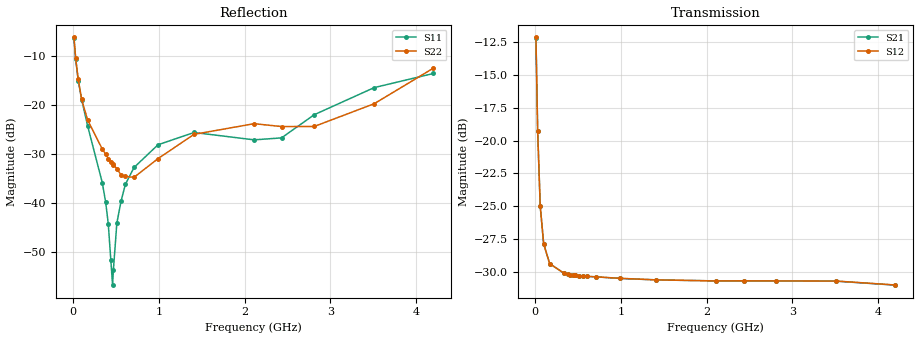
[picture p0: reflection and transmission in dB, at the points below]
! Integrated Device Technology
! Corporate Headquarters
! 6024 Silver Creek Valley Road
! San Jose, CA 95138  USA
! Phone:  1-408-284-8200
! Toll Free:  1-800-223-1366
! Webpage:  http://www.idt.com/
! Timing and RF Division
! 515 Groton Road, Suite 102
! Westford, MA 01886-6024
! Device:  F1950
! Description: 7-bit 0.25 dB Digital Step Attenuator
! Frequency:  150.0 -  4000.00 MHz
! Package:  4x4 mm Thin QFN Plastic Package: 24 pin
! Ports:  2 RF, 12 DC
!  Pin  1  = D0
!  Pin  2  = VDD
!  Pin  3  = Vmode
!  Pin  4  = GND
!  Pin  5  = RF1  =  Port 1
!  Pin  6  = GND
!  Pin  7  = GND
!  Pin  8  = GND
!  Pin  9  = GND
!  Pin 10  = GND
!  Pin 11  = GND
!  Pin 12  = GND
!  Pin 13  = GND
!  Pin 14  = RF2  =  Port 2
!  Pin 15  = GND
!  Pin 16  = LE
!  Pin 17  = CLK
!  Pin 18  = DATE
!  Pin 19  = D6
!  Pin 20  = D5
!  Pin 21  = D4
!  Pin 22  = D3
!  Pin 23  = D2
!  Pin 24  = D1
! State:  118
! Atten State:  29.50 dB
! Voltage:  +5.00 Volts
! Current:  Not Measured mA
! Data:  The device was measured on a the F195X evaluation board which has
!  individual transmission lines to the RF pins.  Data was collected
!  using a calibrated network analyzer.  The evaluation board was
!  de-embedded using a TRL calibration technique.
!  The reference plane is the edge of the package pin.
! Misc:  Board 2019
!  Action Tracker AT0250
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# GHz S dB R 50
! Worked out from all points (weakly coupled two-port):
!   420 points, 10 MHz to 4.2 GHz, reference 50 ohm
!   highest |S21| = -12.14 dB at 10 MHz (marker M1); lowest = -31.0 dB at 4.2 GHz (marker M2)
!   lowest |S11| = -56.7 dB at 460 MHz (marker M3), VSWR 1.00, Z = 49.9 - j0.0336 ohm
!   |S11| at or under -10 dB: 26.67 MHz to end of sweep
!   |S22| runs from -35.0 to -6.2 dB; largest |S21 - S12| = 7.1e-05
!   S11 on the Smith chart (normalised r, x): 10 MHz: 1.96, -1.18; 30 MHz: 1.28, -0.64; 60 MHz: 1.11, -0.36; 410 MHz: 1.00, -0.01; 4.2 GHz: 0.69, +0.17
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0.01  -6.41 -29.1  -12.14 -42.3  -12.13 -42.2  -6.21 -29.8
0.03  -10.64 -51.0  -19.27 -62.6  -19.27 -62.6  -10.49 -53.0
0.06  -15.03 -63.6  -24.99 -55.9  -24.99 -55.9  -14.78 -65.6
0.1  -18.90 -70.4  -27.87 -42.2  -27.87 -42.2  -18.86 -71.2
0.17  -24.29 -71.9  -29.38 -28.5  -29.39 -28.5  -23.07 -77.0
0.34  -35.79 -70.3  -30.13 -17.3  -30.12 -17.3  -28.96 -85.9
0.38  -39.83 -70.1  -30.18 -16.3  -30.19 -16.3  -29.99 -87.6
0.41  -44.18 -76.7  -30.22 -15.6  -30.22 -15.7  -30.88 -89.2
0.44  -51.63 -96.9  -30.25 -15.1  -30.25 -15.1  -31.69 -93.4
0.46  -56.67 -166.7  -30.26 -14.9  -30.26 -14.9  -32.09 -96.8
0.47  -53.50 159.1  -30.27 -14.7  -30.27 -14.7  -32.24 -98.5
0.51  -44.03 137.8  -30.30 -14.3  -30.30 -14.3  -32.92 -102.7
0.56  -39.49 134.0  -30.32 -13.9  -30.33 -13.9  -34.28 -110.9
0.61  -36.11 135.2  -30.36 -13.6  -30.35 -13.6  -34.53 -122.0
0.71  -32.71 136.8  -30.39 -13.4  -30.39 -13.4  -34.72 -141.7
0.99  -28.08 146.3  -30.51 -13.9  -30.50 -14.0  -30.90 178.8
1.41  -25.58 161.8  -30.62 -15.7  -30.62 -15.7  -25.96 159.8
2.11  -27.08 155.9  -30.70 -19.9  -30.70 -20.0  -23.79 141.5
2.43  -26.68 124.1  -30.70 -21.6  -30.69 -21.6  -24.37 130.6
2.81  -21.97 104.0  -30.70 -24.6  -30.70 -24.6  -24.36 115.2
3.51  -16.44 116.5  -30.72 -29.3  -30.71 -29.4  -19.72 112.7
4.2  -13.56 145.1  -31.02 -31.5  -31.01 -31.6  -12.48 126.9
